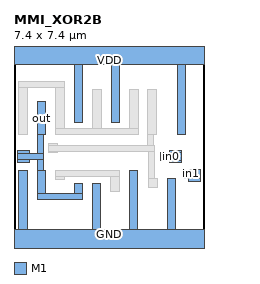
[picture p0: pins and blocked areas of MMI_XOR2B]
MACRO MMI_XOR2B
	CLASS CORE ;
	FOREIGN MMI_XOR2B 0 0 ;
	SIZE 7.4 BY 7.4 ;
	SYMMETRY X Y ;
	SITE CORE1 ;
	PIN out
		DIRECTION output ;
		USE SIGNAL ;
		PORT
			LAYER M1 ;
			RECT 0.9 4.18 1.24 5.46 ;
			LAYER M1 ;
			RECT 0.145 3.445 0.595 3.555 ;
			LAYER M1 ;
			RECT 0.9 3.445 1.13 4.18 ;
			LAYER M1 ;
			RECT 0.145 3.215 1.13 3.445 ;
			LAYER M1 ;
			RECT 0.145 3.105 0.595 3.215 ;
			LAYER M1 ;
			RECT 0.9 2.79 1.13 3.215 ;
			LAYER M1 ;
			RECT 0.9 1.88 1.24 2.79 ;
			LAYER M1 ;
			RECT 2.34 1.88 2.68 2.29 ;
			LAYER M1 ;
			RECT 0.9 1.65 2.68 1.88 ;
		END
		AntennaDiffArea 1.932 ;
	END out
	PIN in1
		DIRECTION input ;
		USE SIGNAL ;
		PORT
			LAYER M1 ;
			RECT 6.55 2.815 6.89 2.84 ;
			LAYER M1 ;
			RECT 6.55 2.5 7.255 2.815 ;
			LAYER M1 ;
			RECT 6.61 2.47 7.255 2.5 ;
			LAYER M1 ;
			RECT 6.805 2.365 7.255 2.47 ;
		END
		AntennaGateArea 1.4076 ;
	END in1
	PIN GND
		DIRECTION inout ;
		USE GROUND ;
		PORT
			LAYER M1 ;
			RECT 0.18 0.5 0.52 2.79 ;
			LAYER M1 ;
			RECT 3.04 0.5 3.38 2.29 ;
			LAYER M1 ;
			RECT 4.48 0.5 4.82 2.79 ;
			LAYER M1 ;
			RECT 5.96 0.5 6.3 2.49 ;
			LAYER M1 ;
			RECT 0 -0.5 7.4 0.5 ;
		END
	END GND
	PIN VDD
		DIRECTION inout ;
		USE POWER ;
		PORT
			LAYER M1 ;
			RECT 0 6.9 7.4 7.9 ;
			LAYER M1 ;
			RECT 2.34 4.66 2.68 6.9 ;
			LAYER M1 ;
			RECT 3.78 4.66 4.12 6.9 ;
			LAYER M1 ;
			RECT 6.35 4.18 6.69 6.9 ;
		END
	END VDD
	PIN in0
		DIRECTION input ;
		USE SIGNAL ;
		PORT
			LAYER M1 ;
			RECT 6.065 3.5 6.515 3.555 ;
			LAYER M1 ;
			RECT 5.7 3.16 6.515 3.5 ;
			LAYER M1 ;
			RECT 6.065 3.105 6.515 3.16 ;
		END
		AntennaGateArea 1.4076 ;
	END in0
	OBS
		LAYER M1 ;
		RECT 0.18 6.01 1.96 6.24 ;
		LAYER M1 ;
		RECT 0.18 4.18 0.52 6.01 ;
		LAYER M1 ;
		RECT 1.62 4.41 1.96 6.01 ;
		LAYER M1 ;
		RECT 3.06 4.41 3.4 5.94 ;
		LAYER M1 ;
		RECT 4.5 4.41 4.84 5.94 ;
		LAYER M1 ;
		RECT 1.62 4.18 4.84 4.41 ;
		LAYER M1 ;
		RECT 5.2 4.18 5.54 5.94 ;
		LAYER M1 ;
		RECT 1.36 3.77 1.7 3.825 ;
		LAYER M1 ;
		RECT 5.2 3.77 5.43 4.18 ;
		LAYER M1 ;
		RECT 1.36 3.54 5.47 3.77 ;
		LAYER M1 ;
		RECT 1.36 3.485 1.7 3.54 ;
		LAYER M1 ;
		RECT 1.62 2.56 4.1 2.79 ;
		LAYER M1 ;
		RECT 1.62 2.45 1.96 2.56 ;
		LAYER M1 ;
		RECT 3.76 1.95 4.1 2.56 ;
		LAYER M1 ;
		RECT 5.24 2.49 5.47 3.54 ;
		LAYER M1 ;
		RECT 5.24 2.11 5.58 2.49 ;
	END
END MMI_XOR2B
